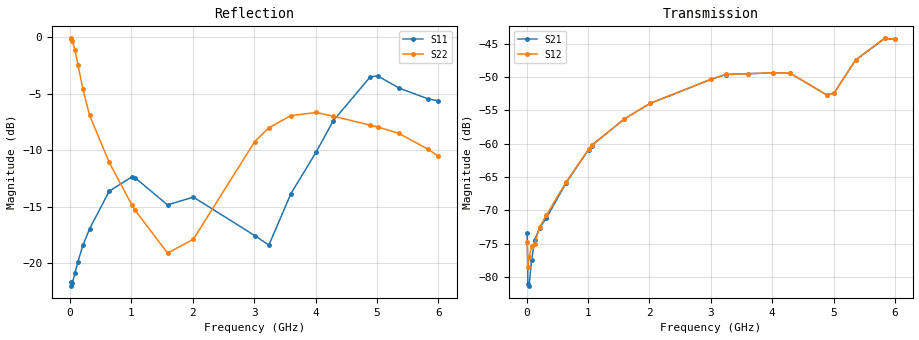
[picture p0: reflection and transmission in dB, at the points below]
!Agilent Technologies,N5230A,MY45001650,A.07.50.48
!Agilent N5230A: A.07.50.48
!Date: Saturday, July 08, 2017 15:44:47
!Correction: S11(Full 2 Port(1,2))
!S21(Full 2 Port(1,2))
!S12(Full 2 Port(1,2))
!S22(Full 2 Port(1,2))
!S2P File: Measurements: S11, S21, S12, S22:
# Hz S  dB  R 50
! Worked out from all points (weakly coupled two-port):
!   600 points, 10 MHz to 6 GHz, reference 50 ohm
!   highest |S21| = -44.22 dB at 5.83 GHz (marker M1); lowest = -81.3 dB at 40 MHz (marker M2)
!   lowest |S11| = -22.0 dB at 20 MHz (marker M3), VSWR 1.17, Z = 58.5 - j1.29 ohm
!   |S11| at or under -10 dB: start of sweep to 4.028 GHz
!   |S22| runs from -19.5 to -0.1 dB; largest |S21 - S12| = 0.00017
!   S11 on the Smith chart (normalised r, x): 10 MHz: 1.18, -0.02; 1.06 GHz: 0.61, -0.01; 4.29 GHz: 1.00, +0.94; 4.89 GHz: 2.80, +2.38; 6 GHz: 2.75, -1.03
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1e7  -21.69 -6.4  -73.43 172.0  -74.65 136.4  -0.12 -5.7
2e7  -21.98 -7.9  -81.02 124.4  -78.46 90.4  -0.15 -11.0
4e7  -21.75 -13.9  -81.27 76.8  -76.99 88.1  -0.35 -21.6
8e7  -20.87 -28.2  -77.48 48.2  -75.39 86.2  -1.12 -40.8
1.3e8  -19.85 -43.0  -74.46 55.1  -75.06 55.7  -2.46 -60.2
2.1e8  -18.42 -64.2  -72.62 46.5  -72.53 49.9  -4.59 -83.9
3.2e8  -16.95 -89.1  -71.17 44.2  -70.73 45.4  -6.93 -106.6
6.4e8  -13.62 -135.2  -65.91 43.9  -65.78 45.0  -11.09 -145.1
1.01e9  -12.36 -171.1  -60.86 24.2  -60.81 24.4  -14.86 -167.6
1.06e9  -12.44 -177.6  -60.27 21.0  -60.21 21.2  -15.30 -170.4
1.59e9  -14.84 160.2  -56.29 -20.0  -56.28 -19.7  -19.10 -178.3
2.01e9  -14.15 157.3  -53.96 -51.0  -53.94 -51.2  -17.88 -174.5
3.01e9  -17.55 150.1  -50.32 -139.3  -50.30 -139.2  -9.24 148.4
3.24e9  -18.39 160.3  -49.63 -164.6  -49.60 -164.6  -8.02 139.8
3.6e9  -13.84 142.0  -49.50 157.3  -49.50 157.4  -6.95 126.5
4.01e9  -10.17 88.7  -49.36 118.7  -49.36 118.8  -6.67 109.5
4.29e9  -7.40 65.0  -49.41 88.8  -49.40 88.9  -7.00 96.7
4.89e9  -3.53 20.8  -52.69 50.8  -52.69 51.0  -7.79 60.4
5.01e9  -3.43 13.6  -52.37 53.4  -52.38 53.5  -7.94 53.0
5.36e9  -4.51 -2.6  -47.45 40.4  -47.42 40.7  -8.52 29.6
5.83e9  -5.46 -6.9  -44.22 -12.1  -44.20 -12.1  -9.91 -0.6
6e9  -5.64 -15.2  -44.35 -26.0  -44.31 -26.1  -10.53 -9.5
